One B-rep face of a CAD part: STEP entity #2111.
In plain terms, the planar face has unit normal (0, 0, -1).
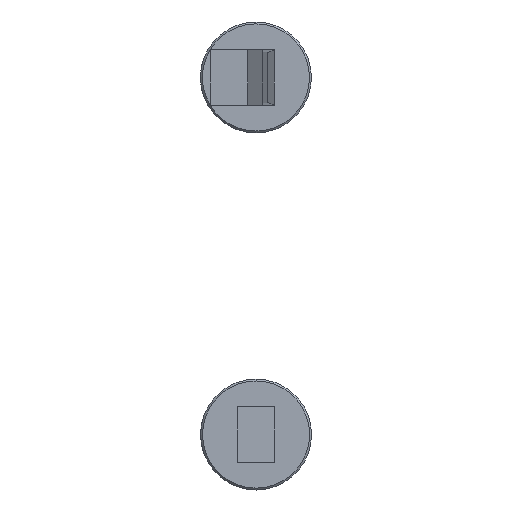
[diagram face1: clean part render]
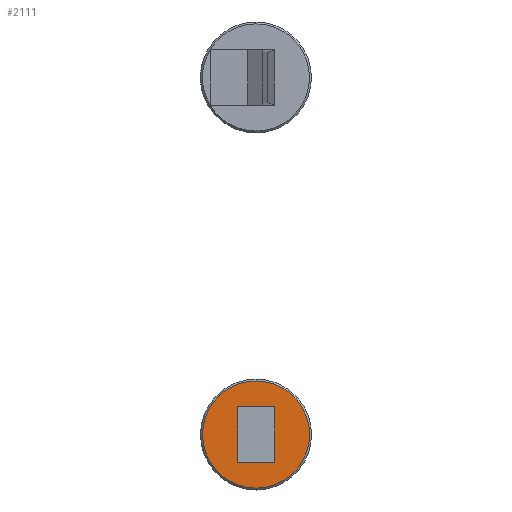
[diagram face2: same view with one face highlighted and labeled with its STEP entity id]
Its self-contained STEP definition (entity closure, numbers rounded to 3 decimals):
#142 = AXIS2_PLACEMENT_3D ( 'NONE', #346, #312, #306 ) ;
#156 = CIRCLE ( 'NONE', #142, 5.8 ) ;
#166 = AXIS2_PLACEMENT_3D ( 'NONE', #368, #361, #381 ) ;
#306 = DIRECTION ( 'NONE',  ( 1., 0., 0. ) ) ;
#312 = DIRECTION ( 'NONE',  ( 0., 0., -1. ) ) ;
#326 = PLANE ( 'NONE',  #166 ) ;
#346 = CARTESIAN_POINT ( 'NONE',  ( 0., 0., 0. ) ) ;
#361 = DIRECTION ( 'NONE',  ( 0., 0., 1. ) ) ;
#366 = FACE_OUTER_BOUND ( 'NONE', #781, .T. ) ;
#367 = FACE_BOUND ( 'NONE', #774, .T. ) ;
#368 = CARTESIAN_POINT ( 'NONE',  ( 0., 0., 0. ) ) ;
#381 = DIRECTION ( 'NONE',  ( 1., 0., 0. ) ) ;
#580 = VECTOR ( 'NONE', #2937, 1000. ) ;
#774 = EDGE_LOOP ( 'NONE', ( #1708, #1658, #1682, #1657 ) ) ;
#781 = EDGE_LOOP ( 'NONE', ( #1892, #1884 ) ) ;
#1504 = EDGE_CURVE ( 'NONE', #1822, #1854, #2714, .T. ) ;
#1525 = EDGE_CURVE ( 'NONE', #1854, #1794, #2782, .T. ) ;
#1528 = EDGE_CURVE ( 'NONE', #1841, #1822, #2784, .T. ) ;
#1529 = EDGE_CURVE ( 'NONE', #1809, #1811, #2020, .T. ) ;
#1547 = EDGE_CURVE ( 'NONE', #1794, #1841, #2917, .T. ) ;
#1657 = ORIENTED_EDGE ( 'NONE', *, *, #1547, .T. ) ;
#1658 = ORIENTED_EDGE ( 'NONE', *, *, #1504, .T. ) ;
#1682 = ORIENTED_EDGE ( 'NONE', *, *, #1525, .T. ) ;
#1708 = ORIENTED_EDGE ( 'NONE', *, *, #1528, .T. ) ;
#1794 = VERTEX_POINT ( 'NONE', #2530 ) ;
#1809 = VERTEX_POINT ( 'NONE', #2531 ) ;
#1811 = VERTEX_POINT ( 'NONE', #2546 ) ;
#1822 = VERTEX_POINT ( 'NONE', #2547 ) ;
#1841 = VERTEX_POINT ( 'NONE', #2580 ) ;
#1854 = VERTEX_POINT ( 'NONE', #2603 ) ;
#1884 = ORIENTED_EDGE ( 'NONE', *, *, #2096, .T. ) ;
#1892 = ORIENTED_EDGE ( 'NONE', *, *, #1529, .T. ) ;
#1988 = VECTOR ( 'NONE', #2785, 1000. ) ;
#1996 = AXIS2_PLACEMENT_3D ( 'NONE', #2810, #2788, #2790 ) ;
#2001 = VECTOR ( 'NONE', #2789, 1000. ) ;
#2011 = VECTOR ( 'NONE', #2716, 1000. ) ;
#2020 = CIRCLE ( 'NONE', #1996, 5.8 ) ;
#2096 = EDGE_CURVE ( 'NONE', #1811, #1809, #156, .T. ) ;
#2111 = ADVANCED_FACE ( 'NONE', ( #366, #367 ), #326, .F. ) ;
#2530 = CARTESIAN_POINT ( 'NONE',  ( 3., 2., 0. ) ) ;
#2531 = CARTESIAN_POINT ( 'NONE',  ( 5.8, 0., 0. ) ) ;
#2546 = CARTESIAN_POINT ( 'NONE',  ( -5.8, 0., 0. ) ) ;
#2547 = CARTESIAN_POINT ( 'NONE',  ( -3., -2., 0. ) ) ;
#2580 = CARTESIAN_POINT ( 'NONE',  ( -3., 2., 0. ) ) ;
#2603 = CARTESIAN_POINT ( 'NONE',  ( 3., -2., 0. ) ) ;
#2714 = LINE ( 'NONE', #2729, #2011 ) ;
#2716 = DIRECTION ( 'NONE',  ( 1., 0., 0. ) ) ;
#2729 = CARTESIAN_POINT ( 'NONE',  ( -3., -2., 0. ) ) ;
#2782 = LINE ( 'NONE', #2823, #2001 ) ;
#2784 = LINE ( 'NONE', #2798, #1988 ) ;
#2785 = DIRECTION ( 'NONE',  ( 0., -1., 0. ) ) ;
#2788 = DIRECTION ( 'NONE',  ( 0., 0., -1. ) ) ;
#2789 = DIRECTION ( 'NONE',  ( 0., 1., 0. ) ) ;
#2790 = DIRECTION ( 'NONE',  ( 1., 0., 0. ) ) ;
#2798 = CARTESIAN_POINT ( 'NONE',  ( -3., 2., 0. ) ) ;
#2810 = CARTESIAN_POINT ( 'NONE',  ( 0., 0., 0. ) ) ;
#2823 = CARTESIAN_POINT ( 'NONE',  ( 3., 2., 0. ) ) ;
#2917 = LINE ( 'NONE', #2942, #580 ) ;
#2937 = DIRECTION ( 'NONE',  ( -1., 0., 0. ) ) ;
#2942 = CARTESIAN_POINT ( 'NONE',  ( -3., 2., 0. ) ) ;
